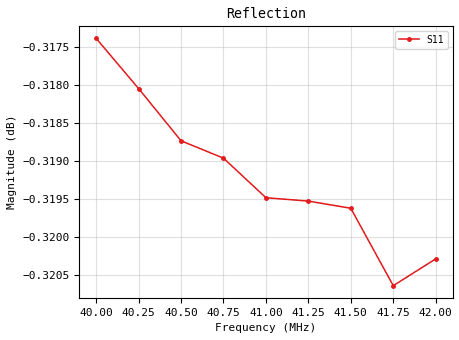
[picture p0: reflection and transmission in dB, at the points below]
# Hz S RI R 50
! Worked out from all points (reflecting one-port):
!   9 points, 40 MHz to 42 MHz, reference 50 ohm
!   lowest |S11| = -0.3 dB at 42 MHz (marker M1), VSWR 54.20, Z = 2.77 + j70.6 ohm
!   phase of S11 starts at 76 deg and turns -5 deg over the sweep
4e7  0.2391 0.934
4.025e7  0.2495 0.9312
4.05e7  0.2598 0.9283
4.075e7  0.2702 0.9253
4.1e7  0.2804 0.9222
4.125e7  0.2907 0.919
4.15e7  0.3009 0.9157
4.175e7  0.311 0.9122
4.2e7  0.3212 0.9087
